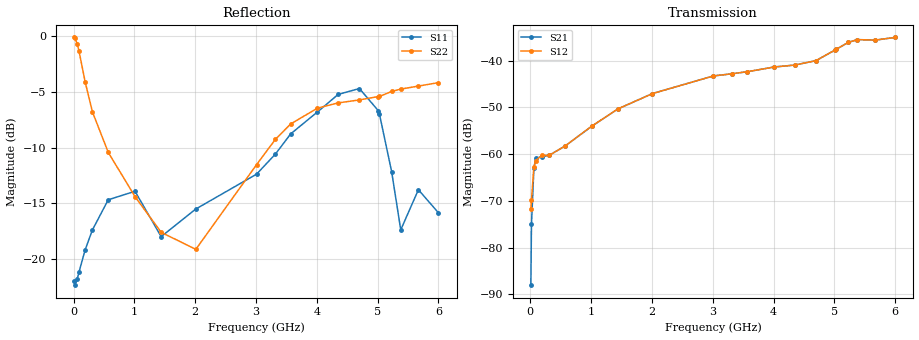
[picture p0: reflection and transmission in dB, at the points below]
!Agilent Technologies,N5230A,MY45001650,A.07.50.48
!Agilent N5230A: A.07.50.48
!Date: Saturday, July 08, 2017 15:55:05
!Correction: S11(Full 2 Port(1,2))
!S21(Full 2 Port(1,2))
!S12(Full 2 Port(1,2))
!S22(Full 2 Port(1,2))
!S2P File: Measurements: S11, S21, S12, S22:
# Hz S  dB  R 50
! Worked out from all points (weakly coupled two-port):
!   600 points, 10 MHz to 6 GHz, reference 50 ohm
!   highest |S21| = -34.99 dB at 6 GHz (marker M1); lowest = -88.1 dB at 10 MHz (marker M2)
!   lowest |S11| = -22.3 dB at 20 MHz (marker M3), VSWR 1.17, Z = 58.1 - j1.46 ohm
!   |S11| at or under -10 dB: start of sweep to 3.385 GHz; 5.166 GHz to end of sweep
!   |S22| runs from -19.6 to -0.1 dB; largest |S21 - S12| = 0.00029
!   S11 on the Smith chart (normalised r, x): 10 MHz: 1.17, -0.03; 1.44 GHz: 0.79, +0.07; 3.57 GHz: 0.67, +0.55; 4.35 GHz: 2.18, +1.53; 5.03 GHz: 1.88, -1.05; 6 GHz: 1.23, +0.28
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1e7  -21.95 -8.0  -88.05 -132.2  -71.70 77.8  -0.11 -5.5
2e7  -22.34 -9.4  -75.01 115.4  -69.73 65.8  -0.14 -10.5
6e7  -21.80 -23.0  -62.96 26.4  -62.69 28.9  -0.69 -30.2
9e7  -21.14 -33.4  -60.91 3.6  -61.36 2.4  -1.37 -43.0
1.9e8  -19.18 -62.7  -60.54 -43.9  -60.28 -42.2  -4.10 -74.9
3.1e8  -17.38 -91.1  -60.25 -75.8  -60.26 -75.6  -6.80 -99.0
5.7e8  -14.68 -133.8  -58.29 -122.9  -58.27 -122.3  -10.43 -130.0
1.01e9  -13.92 179.6  -54.04 177.9  -54.01 178.0  -14.40 -155.2
1.44e9  -17.99 158.3  -50.33 127.0  -50.31 126.9  -17.60 -169.3
2.01e9  -15.51 170.3  -47.01 62.2  -47.03 62.2  -19.13 -169.9
3.01e9  -12.38 145.7  -43.25 -37.2  -43.26 -37.2  -11.52 168.5
3.32e9  -10.57 129.9  -42.78 -67.4  -42.77 -67.3  -9.25 159.7
3.57e9  -8.77 102.3  -42.35 -89.4  -42.34 -89.4  -7.88 153.2
4.01e9  -6.80 52.7  -41.33 -129.1  -41.34 -129.1  -6.46 139.6
4.35e9  -5.23 26.7  -40.91 -158.7  -40.92 -158.7  -5.99 128.3
4.7e9  -4.70 -1.7  -39.97 176.6  -39.96 176.6  -5.72 114.6
5.01e9  -6.68 -28.4  -37.72 151.5  -37.70 151.5  -5.42 101.6
5.03e9  -7.00 -30.1  -37.56 149.6  -37.54 149.6  -5.41 100.5
5.23e9  -12.15 -40.6  -36.07 126.2  -36.06 126.2  -4.96 92.6
5.38e9  -17.38 -16.0  -35.47 105.8  -35.46 105.8  -4.75 84.7
5.67e9  -13.78 17.3  -35.59 72.5  -35.57 72.4  -4.48 69.7
6e9  -15.85 44.1  -34.99 40.9  -35.00 41.0  -4.17 52.0
